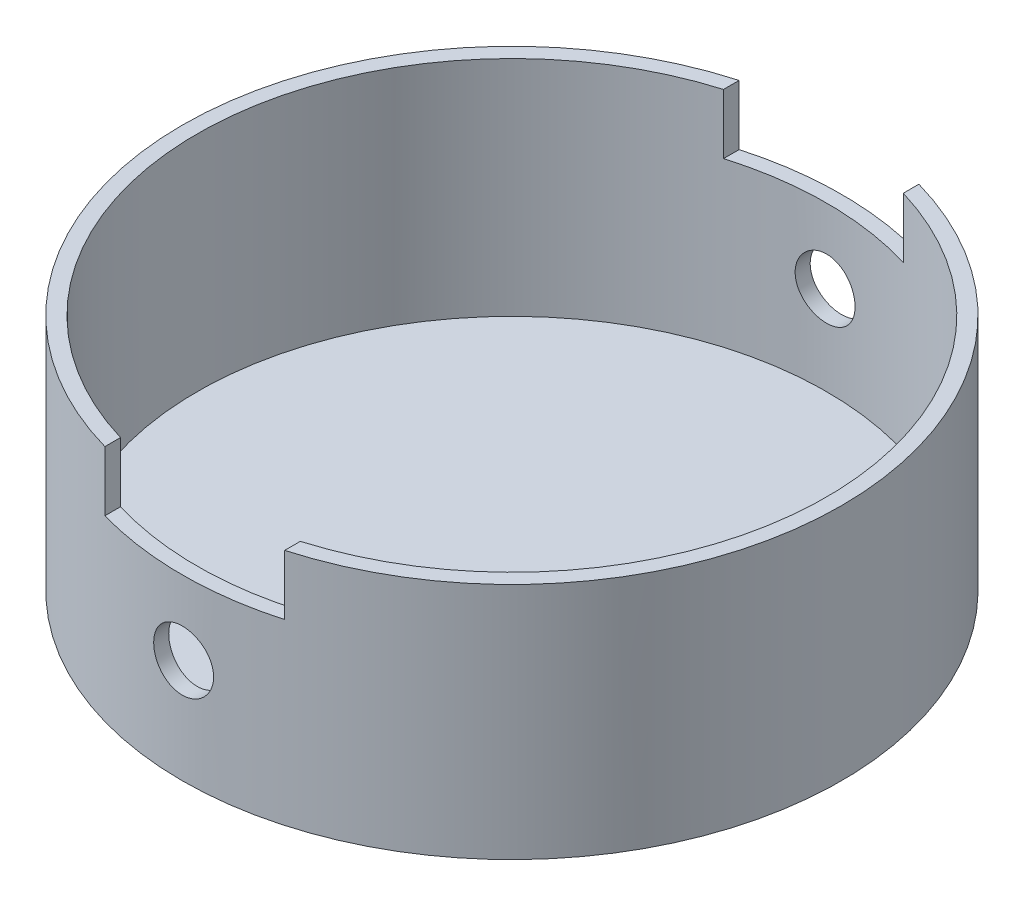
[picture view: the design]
ISO-10303-21;
HEADER;
FILE_DESCRIPTION(('STEP AP214'),'2;1');
FILE_NAME('part.step','',(''),(''),'','','');
FILE_SCHEMA(('AUTOMOTIVE_DESIGN { 1 0 10303 214 1 1 1 1 }'));
ENDSEC;
DATA;
#1=APPLICATION_CONTEXT('core data for automotive mechanical design processes');
#2=APPLICATION_PROTOCOL_DEFINITION('international standard','automotive_design',2000,#1);
#3=PRODUCT_CONTEXT('',#1,'mechanical');
#4=PRODUCT('Part','Part','',(#3));
#5=PRODUCT_RELATED_PRODUCT_CATEGORY('part','',(#4));
#6=PRODUCT_DEFINITION_FORMATION('','',#4);
#7=PRODUCT_DEFINITION_CONTEXT('part definition',#1,'design');
#8=PRODUCT_DEFINITION('design','',#6,#7);
#9=PRODUCT_DEFINITION_SHAPE('','',#8);
#10=(LENGTH_UNIT() NAMED_UNIT(*) SI_UNIT(.MILLI.,.METRE.));
#11=(NAMED_UNIT(*) PLANE_ANGLE_UNIT() SI_UNIT($,.RADIAN.));
#12=(NAMED_UNIT(*) SI_UNIT($,.STERADIAN.) SOLID_ANGLE_UNIT());
#13=UNCERTAINTY_MEASURE_WITH_UNIT(LENGTH_MEASURE(1.E-05),#10,'distance_accuracy_value','');
#14=(GEOMETRIC_REPRESENTATION_CONTEXT(3) GLOBAL_UNCERTAINTY_ASSIGNED_CONTEXT((#13)) GLOBAL_UNIT_ASSIGNED_CONTEXT((#10,
#11,#12)) REPRESENTATION_CONTEXT('',''));
#15=CARTESIAN_POINT('',(0.,0.,0.));
#16=DIRECTION('',(0.,0.,1.));
#17=DIRECTION('',(1.,0.,0.));
#18=AXIS2_PLACEMENT_3D('',#15,#16,#17);
#19=CARTESIAN_POINT('',(0.,50.4952,0.));
#20=DIRECTION('',(0.,1.,0.));
#21=DIRECTION('',(0.,0.,1.));
#22=AXIS2_PLACEMENT_3D('',#19,#20,#21);
#23=PLANE('',#22);
#24=DIRECTION('',(0.,0.,1.));
#25=VECTOR('',#24,1.);
#26=CARTESIAN_POINT('',(-19.05,50.4952,-69.85));
#27=LINE('',#26,#25);
#28=CARTESIAN_POINT('',(-19.05,50.4952,-67.2020833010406));
#29=VERTEX_POINT('',#28);
#30=CARTESIAN_POINT('',(-19.05,50.4952,-63.8956424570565));
#31=VERTEX_POINT('',#30);
#32=EDGE_CURVE('E112',#29,#31,#27,.T.);
#33=ORIENTED_EDGE('',*,*,#32,.F.);
#34=CARTESIAN_POINT('',(0.,50.4952,0.));
#35=DIRECTION('',(0.,1.,0.));
#36=DIRECTION('',(0.,0.,1.));
#37=AXIS2_PLACEMENT_3D('',#34,#35,#36);
#38=CIRCLE('',#37,69.85);
#39=CARTESIAN_POINT('',(-19.05,50.4952,67.2020833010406));
#40=VERTEX_POINT('',#39);
#41=EDGE_CURVE('E150',#29,#40,#38,.T.);
#42=ORIENTED_EDGE('',*,*,#41,.T.);
#43=CARTESIAN_POINT('',(-19.05,50.4952,63.8956424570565));
#44=VERTEX_POINT('',#43);
#45=EDGE_CURVE('E190',#44,#40,#27,.T.);
#46=ORIENTED_EDGE('',*,*,#45,.F.);
#47=CARTESIAN_POINT('',(0.,50.4952,0.));
#48=DIRECTION('',(0.,1.,0.));
#49=DIRECTION('',(0.,0.,1.));
#50=AXIS2_PLACEMENT_3D('',#47,#48,#49);
#51=CIRCLE('',#50,66.675);
#52=EDGE_CURVE('E145',#31,#44,#51,.T.);
#53=ORIENTED_EDGE('',*,*,#52,.F.);
#54=EDGE_LOOP('',(#33,#42,#46,#53));
#55=FACE_BOUND('',#54,.T.);
#56=ADVANCED_FACE('F31',(#55),#23,.T.);
#57=CARTESIAN_POINT('',(0.,50.4952,0.));
#58=DIRECTION('',(0.,-1.,0.));
#59=DIRECTION('',(0.,0.,-1.));
#60=AXIS2_PLACEMENT_3D('',#57,#58,#59);
#61=CYLINDRICAL_SURFACE('',#60,69.85);
#62=CARTESIAN_POINT('',(0.,28.4226,-69.85));
#63=CARTESIAN_POINT('',(-0.178010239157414,28.4226016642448,-69.8500004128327));
#64=CARTESIAN_POINT('',(-0.355994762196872,28.4151118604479,-69.8493181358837));
#65=CARTESIAN_POINT('',(-0.710752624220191,28.3852076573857,-69.8466089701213));
#66=CARTESIAN_POINT('',(-0.887525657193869,28.3627896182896,-69.8445817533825));
#67=CARTESIAN_POINT('',(-1.23868383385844,28.3031624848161,-69.8392370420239));
#68=CARTESIAN_POINT('',(-1.41306691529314,28.2659413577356,-69.8359184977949));
#69=CARTESIAN_POINT('',(-1.75812567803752,28.1769632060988,-69.8280837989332));
#70=CARTESIAN_POINT('',(-1.92879997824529,28.1252008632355,-69.8235672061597));
#71=CARTESIAN_POINT('',(-2.26500272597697,28.007576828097,-69.8134694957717));
#72=CARTESIAN_POINT('',(-2.43053592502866,27.9417286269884,-69.8078893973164));
#73=CARTESIAN_POINT('',(-2.75551943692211,27.7963497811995,-69.7958169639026));
#74=CARTESIAN_POINT('',(-2.9149674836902,27.7168140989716,-69.7893242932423));
#75=CARTESIAN_POINT('',(-3.22650420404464,27.5446948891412,-69.7756151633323));
#76=CARTESIAN_POINT('',(-3.37859709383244,27.452118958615,-69.7683991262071));
#77=CARTESIAN_POINT('',(-3.67451208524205,27.2545038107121,-69.7534402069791));
#78=CARTESIAN_POINT('',(-3.81833110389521,27.1494599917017,-69.7456971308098));
#79=CARTESIAN_POINT('',(-4.09695134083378,26.9274218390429,-69.7298860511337));
#80=CARTESIAN_POINT('',(-4.23173107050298,26.8104005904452,-69.7218173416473));
#81=CARTESIAN_POINT('',(-4.49101041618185,26.5653888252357,-69.705596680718));
#82=CARTESIAN_POINT('',(-4.61550621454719,26.4373942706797,-69.6974446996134));
#83=CARTESIAN_POINT('',(-4.85324696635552,26.1714168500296,-69.6812936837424));
#84=CARTESIAN_POINT('',(-4.96649554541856,26.0334372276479,-69.6732946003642));
#85=CARTESIAN_POINT('',(-5.1810275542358,25.7483703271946,-69.657670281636));
#86=CARTESIAN_POINT('',(-5.28230655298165,25.6012797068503,-69.6500451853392));
#87=CARTESIAN_POINT('',(-5.47226286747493,25.2988619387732,-69.6353784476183));
#88=CARTESIAN_POINT('',(-5.56092260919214,25.1435237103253,-69.6283376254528));
#89=CARTESIAN_POINT('',(-5.72486936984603,24.8258414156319,-69.6150496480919));
#90=CARTESIAN_POINT('',(-5.8001514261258,24.6634947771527,-69.6088027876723));
#91=CARTESIAN_POINT('',(-5.93673339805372,24.3330488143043,-69.5972873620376));
#92=CARTESIAN_POINT('',(-5.9980386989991,24.1649517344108,-69.5920184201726));
#93=CARTESIAN_POINT('',(-6.10627740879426,23.8241436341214,-69.5826040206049));
#94=CARTESIAN_POINT('',(-6.15320552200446,23.6514309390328,-69.578458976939));
#95=CARTESIAN_POINT('',(-6.271576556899,23.1293042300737,-69.5679269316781));
#96=CARTESIAN_POINT('',(-6.32113859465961,22.7746095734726,-69.5633965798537));
#97=CARTESIAN_POINT('',(-6.36002110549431,22.0621022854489,-69.5598516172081));
#98=CARTESIAN_POINT('',(-6.34934290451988,21.7042897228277,-69.5608368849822));
#99=CARTESIAN_POINT('',(-6.26826208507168,20.9965952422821,-69.5681897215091));
#100=CARTESIAN_POINT('',(-6.19803812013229,20.6466928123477,-69.5745411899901));
#101=CARTESIAN_POINT('',(-6.00011593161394,19.963675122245,-69.5918880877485));
#102=CARTESIAN_POINT('',(-5.87241705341,19.6305600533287,-69.6028835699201));
#103=CARTESIAN_POINT('',(-5.56297669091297,18.9899888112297,-69.6282974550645));
#104=CARTESIAN_POINT('',(-5.38115541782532,18.6825713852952,-69.6427209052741));
#105=CARTESIAN_POINT('',(-4.96868743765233,18.1025502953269,-69.6733612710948));
#106=CARTESIAN_POINT('',(-4.7380395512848,17.8299474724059,-69.6895782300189));
#107=CARTESIAN_POINT('',(-4.23346551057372,17.3262537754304,-69.7220500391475));
#108=CARTESIAN_POINT('',(-3.9593849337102,17.0953175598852,-69.7383048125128));
#109=CARTESIAN_POINT('',(-3.3762631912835,16.6827098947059,-69.7689647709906));
#110=CARTESIAN_POINT('',(-3.06722199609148,16.5010384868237,-69.7833699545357));
#111=CARTESIAN_POINT('',(-2.42284819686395,16.1921254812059,-69.8087112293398));
#112=CARTESIAN_POINT('',(-2.08751208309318,16.0648911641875,-69.8196468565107));
#113=CARTESIAN_POINT('',(-1.4001154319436,15.8685745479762,-69.8368118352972));
#114=CARTESIAN_POINT('',(-1.04805530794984,15.7994908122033,-69.8430413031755));
#115=CARTESIAN_POINT('',(-0.338544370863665,15.7216312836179,-69.8500771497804));
#116=CARTESIAN_POINT('',(0.0188828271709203,15.7126419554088,-69.8509027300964));
#117=CARTESIAN_POINT('',(0.730158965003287,15.7546664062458,-69.847089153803));
#118=CARTESIAN_POINT('',(1.0840079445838,15.8056795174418,-69.8424500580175));
#119=CARTESIAN_POINT('',(1.77747108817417,15.9660836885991,-69.828240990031));
#120=CARTESIAN_POINT('',(2.11710843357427,16.0753753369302,-69.8186794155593));
#121=CARTESIAN_POINT('',(2.77322639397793,16.3491324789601,-69.7956988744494));
#122=CARTESIAN_POINT('',(3.08970657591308,16.5135990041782,-69.7822798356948));
#123=CARTESIAN_POINT('',(3.69149557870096,16.8935705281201,-69.7530393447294));
#124=CARTESIAN_POINT('',(3.97671507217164,17.1092164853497,-69.7372113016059));
#125=CARTESIAN_POINT('',(4.50698344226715,17.5852237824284,-69.7049518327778));
#126=CARTESIAN_POINT('',(4.75203148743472,17.8455860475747,-69.6885203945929));
#127=CARTESIAN_POINT('',(5.1957377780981,18.4045593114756,-69.6568486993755));
#128=CARTESIAN_POINT('',(5.39425633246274,18.703281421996,-69.6416121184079));
#129=CARTESIAN_POINT('',(5.73830771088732,19.3299616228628,-69.6141095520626));
#130=CARTESIAN_POINT('',(5.88384114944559,19.657919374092,-69.6018435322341));
#131=CARTESIAN_POINT('',(6.11756176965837,20.3332069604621,-69.5816911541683));
#132=CARTESIAN_POINT('',(6.2058334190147,20.6805074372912,-69.5737983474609));
#133=CARTESIAN_POINT('',(6.32277396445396,21.3852702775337,-69.5632707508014));
#134=CARTESIAN_POINT('',(6.35144424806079,21.7427324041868,-69.5606358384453));
#135=CARTESIAN_POINT('',(6.34919308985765,22.2777191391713,-69.5608370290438));
#136=CARTESIAN_POINT('',(6.34093956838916,22.4556186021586,-69.5615927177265));
#137=CARTESIAN_POINT('',(6.3095350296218,22.8100690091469,-69.5644490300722));
#138=CARTESIAN_POINT('',(6.28638953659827,22.9866204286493,-69.5665491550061));
#139=CARTESIAN_POINT('',(6.22535142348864,23.3371887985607,-69.5720376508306));
#140=CARTESIAN_POINT('',(6.18745338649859,23.5112047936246,-69.5754264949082));
#141=CARTESIAN_POINT('',(6.09720538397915,23.8553549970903,-69.5833934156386));
#142=CARTESIAN_POINT('',(6.04486071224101,24.0254906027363,-69.5879710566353));
#143=CARTESIAN_POINT('',(5.92607389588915,24.3607852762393,-69.5981874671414));
#144=CARTESIAN_POINT('',(5.85962791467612,24.5259429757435,-69.6038265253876));
#145=CARTESIAN_POINT('',(5.71315046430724,24.850012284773,-69.6160025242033));
#146=CARTESIAN_POINT('',(5.63312396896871,25.0089261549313,-69.6225391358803));
#147=CARTESIAN_POINT('',(5.46000764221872,25.3195117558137,-69.6363292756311));
#148=CARTESIAN_POINT('',(5.36691324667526,25.4711809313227,-69.6435830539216));
#149=CARTESIAN_POINT('',(5.16837734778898,25.7661028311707,-69.6585980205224));
#150=CARTESIAN_POINT('',(5.06294034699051,25.9093585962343,-69.6663590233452));
#151=CARTESIAN_POINT('',(4.84000302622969,26.1870496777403,-69.6822029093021));
#152=CARTESIAN_POINT('',(4.72245768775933,26.321448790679,-69.690286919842));
#153=CARTESIAN_POINT('',(4.47651818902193,26.5798258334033,-69.7065166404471));
#154=CARTESIAN_POINT('',(4.34812801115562,26.7038075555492,-69.7146623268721));
#155=CARTESIAN_POINT('',(4.08128283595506,26.9406046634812,-69.7307930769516));
#156=CARTESIAN_POINT('',(3.94282174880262,27.0534131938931,-69.7387780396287));
#157=CARTESIAN_POINT('',(3.65693105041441,27.2669407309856,-69.754353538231));
#158=CARTESIAN_POINT('',(3.50950476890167,27.3676641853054,-69.761944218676));
#159=CARTESIAN_POINT('',(3.20629253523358,27.5565926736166,-69.776538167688));
#160=CARTESIAN_POINT('',(3.05048647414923,27.6447655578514,-69.7835399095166));
#161=CARTESIAN_POINT('',(2.73201989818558,27.8076277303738,-69.7967331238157));
#162=CARTESIAN_POINT('',(2.56936191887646,27.88232195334,-69.8029248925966));
#163=CARTESIAN_POINT('',(2.23842723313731,28.0176712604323,-69.8143203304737));
#164=CARTESIAN_POINT('',(2.07015532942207,28.0783380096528,-69.819524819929));
#165=CARTESIAN_POINT('',(1.72912198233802,28.1852567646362,-69.8288031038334));
#166=CARTESIAN_POINT('',(1.55636166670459,28.2315123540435,-69.8328771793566));
#167=CARTESIAN_POINT('',(1.15536287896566,28.3209189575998,-69.8408112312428));
#168=CARTESIAN_POINT('',(0.925970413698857,28.3590134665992,-69.8442435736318));
#169=CARTESIAN_POINT('',(0.46437071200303,28.4098528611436,-69.848837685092));
#170=CARTESIAN_POINT('',(0.232163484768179,28.4225978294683,-69.8499994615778));
#171=CARTESIAN_POINT('',(0.,28.4226,-69.85));
#172=B_SPLINE_CURVE_WITH_KNOTS('',3,(#62,#63,#64,#65,#66,#67,#68,#69,#70,#71,#72,#73,#74,#75,
#76,#77,#78,#79,#80,#81,#82,#83,#84,#85,#86,#87,#88,#89,#90,#91,#92,#93,#94,#95,#96,#97,#98,#99,
#100,#101,#102,#103,#104,#105,#106,#107,#108,#109,#110,#111,#112,#113,#114,#115,#116,#117,#118,
#119,#120,#121,#122,#123,#124,#125,#126,#127,#128,#129,#130,#131,#132,#133,#134,#135,#136,#137,
#138,#139,#140,#141,#142,#143,#144,#145,#146,#147,#148,#149,#150,#151,#152,#153,#154,#155,#156,
#157,#158,#159,#160,#161,#162,#163,#164,#165,#166,#167,#168,#169,#170,#171),.UNSPECIFIED.,.T.,
.F.,(4,2,2,2,2,2,2,2,2,2,2,2,2,2,2,2,2,2,2,2,2,2,2,2,2,2,2,2,2,2,2,2,2,2,2,2,2,2,2,2,2,2,2,2,2,
2,2,2,2,2,2,2,2,2,4),(0.,0.533827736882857,1.06778568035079,1.60217854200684,2.13676710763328,
2.67084592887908,3.20512173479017,3.73908755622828,4.27325106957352,4.80864243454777,
5.34423166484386,5.8796476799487,6.41526128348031,6.95161365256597,7.48816457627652,
8.02450841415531,8.56104957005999,9.62999055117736,10.6989080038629,11.7646297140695,
12.8303635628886,13.8976763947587,14.9650150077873,16.036237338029,17.1074605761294,
18.1788270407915,19.250167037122,20.3176981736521,21.3852174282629,22.4509215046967,
23.5166455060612,24.5853395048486,25.6540556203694,26.7259402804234,27.7978125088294,
28.8680999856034,29.9383625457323,30.4721205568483,31.0056806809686,31.539436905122,
32.0729977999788,32.6067040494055,33.1402152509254,33.6739132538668,34.2074171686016,
34.742981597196,35.2783502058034,35.8140452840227,36.3495426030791,36.8863878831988,
37.4230362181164,37.9592366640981,38.495303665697,39.1915316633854,39.8877573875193),.UNSPECIFIED.);
#173=CARTESIAN_POINT('',(0.,28.4226,-69.85));
#174=VERTEX_POINT('',#173);
#175=EDGE_CURVE('E134',#174,#174,#172,.T.);
#176=ORIENTED_EDGE('',*,*,#175,.T.);
#177=EDGE_LOOP('',(#176));
#178=FACE_BOUND('',#177,.T.);
#179=CARTESIAN_POINT('',(6.35,22.0726,69.5607648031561));
#180=CARTESIAN_POINT('',(6.35000166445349,21.8945914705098,69.5607643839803));
#181=CARTESIAN_POINT('',(6.34251200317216,21.716608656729,69.5614495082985));
#182=CARTESIAN_POINT('',(6.31260838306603,21.3618542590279,69.5641697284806));
#183=CARTESIAN_POINT('',(6.2901907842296,21.1850829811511,69.5662051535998));
#184=CARTESIAN_POINT('',(6.23056485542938,20.8339283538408,69.5715707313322));
#185=CARTESIAN_POINT('',(6.19334449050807,20.6595470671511,69.5749019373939));
#186=CARTESIAN_POINT('',(6.10436821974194,20.3144919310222,69.5827649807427));
#187=CARTESIAN_POINT('',(6.05260699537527,20.1438194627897,69.5872972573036));
#188=CARTESIAN_POINT('',(5.93498566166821,19.807620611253,69.5974275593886));
#189=CARTESIAN_POINT('',(5.86913906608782,19.6420894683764,69.6030245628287));
#190=CARTESIAN_POINT('',(5.7237638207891,19.3171098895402,69.615130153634));
#191=CARTESIAN_POINT('',(5.6442301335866,19.1576637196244,69.6216390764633));
#192=CARTESIAN_POINT('',(5.472115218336,18.8461304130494,69.6353782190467));
#193=CARTESIAN_POINT('',(5.37954158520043,18.69403906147,69.6426080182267));
#194=CARTESIAN_POINT('',(5.18193124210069,18.3981267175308,69.6575904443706));
#195=CARTESIAN_POINT('',(5.07688993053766,18.2543088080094,69.6653432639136));
#196=CARTESIAN_POINT('',(4.85485427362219,17.9756870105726,69.6811689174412));
#197=CARTESIAN_POINT('',(4.73783273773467,17.8409048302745,69.6892424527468));
#198=CARTESIAN_POINT('',(4.49281987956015,17.5816205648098,69.7054671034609));
#199=CARTESIAN_POINT('',(4.36482451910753,17.4571222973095,69.7136182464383));
#200=CARTESIAN_POINT('',(4.09884499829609,17.2193767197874,69.7297620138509));
#201=CARTESIAN_POINT('',(3.96086408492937,17.1061257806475,69.7377546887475));
#202=CARTESIAN_POINT('',(3.67579412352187,16.891589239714,69.7533613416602));
#203=CARTESIAN_POINT('',(3.52870173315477,16.7903080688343,69.7609751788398));
#204=CARTESIAN_POINT('',(3.22628259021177,16.6003493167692,69.7756156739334));
#205=CARTESIAN_POINT('',(3.07094489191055,16.5116890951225,69.7826415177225));
#206=CARTESIAN_POINT('',(2.753263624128,16.3477413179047,69.7958976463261));
#207=CARTESIAN_POINT('',(2.59091748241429,16.2724587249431,69.802127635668));
#208=CARTESIAN_POINT('',(2.26047253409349,16.1358756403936,69.8136093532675));
#209=CARTESIAN_POINT('',(2.09237597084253,16.0745697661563,69.8188614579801));
#210=CARTESIAN_POINT('',(1.75156900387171,15.9663298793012,69.8282440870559));
#211=CARTESIAN_POINT('',(1.57885692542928,15.9194011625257,69.8323741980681));
#212=CARTESIAN_POINT('',(1.05673284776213,15.8010283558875,69.8428670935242));
#213=CARTESIAN_POINT('',(0.702040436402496,15.7514649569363,69.8473787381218));
#214=CARTESIAN_POINT('',(-0.0104624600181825,15.7125789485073,69.8509094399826));
#215=CARTESIAN_POINT('',(-0.368272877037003,15.7232550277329,69.8499286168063));
#216=CARTESIAN_POINT('',(-1.07597673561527,15.80433249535,69.8426057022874));
#217=CARTESIAN_POINT('',(-1.42589044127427,15.8745573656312,69.8362794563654));
#218=CARTESIAN_POINT('',(-2.10893021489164,16.0724852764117,69.8189927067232));
#219=CARTESIAN_POINT('',(-2.44205609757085,16.2001889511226,69.808032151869));
#220=CARTESIAN_POINT('',(-3.08264041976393,16.5096392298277,69.7826829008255));
#221=CARTESIAN_POINT('',(-3.39006065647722,16.6914645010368,69.7682892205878));
#222=CARTESIAN_POINT('',(-3.9700856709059,17.1039410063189,69.7376900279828));
#223=CARTESIAN_POINT('',(-4.24268960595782,17.3345934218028,69.7214844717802));
#224=CARTESIAN_POINT('',(-4.74637815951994,17.8391706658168,69.6890124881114));
#225=CARTESIAN_POINT('',(-4.97730903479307,18.1132489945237,69.6727460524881));
#226=CARTESIAN_POINT('',(-5.38990699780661,18.6963643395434,69.6420443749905));
#227=CARTESIAN_POINT('',(-5.57157403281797,19.0054013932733,69.6276091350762));
#228=CARTESIAN_POINT('',(-5.88048389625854,19.649774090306,69.6022022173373));
#229=CARTESIAN_POINT('',(-6.00771809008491,19.9851138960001,69.591231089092));
#230=CARTESIAN_POINT('',(-6.204033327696,20.6725185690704,69.5740056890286));
#231=CARTESIAN_POINT('',(-6.27311583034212,21.0245830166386,69.5677512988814));
#232=CARTESIAN_POINT('',(-6.35097071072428,21.7340959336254,69.560687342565));
#233=CARTESIAN_POINT('',(-6.35995778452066,22.0915206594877,69.5598583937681));
#234=CARTESIAN_POINT('',(-6.31792970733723,22.8027913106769,69.5636880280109));
#235=CARTESIAN_POINT('',(-6.26691522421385,23.1566372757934,69.5683465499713));
#236=CARTESIAN_POINT('',(-6.10651143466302,23.8500855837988,69.5826085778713));
#237=CARTESIAN_POINT('',(-5.99722289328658,24.1897114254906,69.5922035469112));
#238=CARTESIAN_POINT('',(-5.72347581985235,24.8458077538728,69.615250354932));
#239=CARTESIAN_POINT('',(-5.55901623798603,25.1622777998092,69.6287022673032));
#240=CARTESIAN_POINT('',(-5.17905490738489,25.7640599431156,69.6579942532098));
#241=CARTESIAN_POINT('',(-4.96341043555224,26.0492815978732,69.6738409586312));
#242=CARTESIAN_POINT('',(-4.48740485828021,26.5795550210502,69.7061148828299));
#243=CARTESIAN_POINT('',(-4.22704283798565,26.8246059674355,69.7225421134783));
#244=CARTESIAN_POINT('',(-3.66806829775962,27.2683184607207,69.754184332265));
#245=CARTESIAN_POINT('',(-3.36934462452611,27.4668402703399,69.7693955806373));
#246=CARTESIAN_POINT('',(-2.74266043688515,27.8108973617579,69.7968374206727));
#247=CARTESIAN_POINT('',(-2.41470026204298,27.956433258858,69.809068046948));
#248=CARTESIAN_POINT('',(-1.73941425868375,28.1901555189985,69.8291549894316));
#249=CARTESIAN_POINT('',(-1.39211815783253,28.278427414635,69.8370178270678));
#250=CARTESIAN_POINT('',(-0.687364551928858,28.3953699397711,69.8475044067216));
#251=CARTESIAN_POINT('',(-0.329907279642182,28.4240419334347,69.8501282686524));
#252=CARTESIAN_POINT('',(0.205078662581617,28.4217945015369,69.8499281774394));
#253=CARTESIAN_POINT('',(0.382981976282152,28.4135418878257,69.8491757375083));
#254=CARTESIAN_POINT('',(0.737440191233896,28.3821385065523,69.8463311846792));
#255=CARTESIAN_POINT('',(0.913995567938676,28.3589932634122,69.8442395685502));
#256=CARTESIAN_POINT('',(1.26457190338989,28.297954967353,69.8387724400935));
#257=CARTESIAN_POINT('',(1.43859190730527,28.2600565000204,69.835396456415));
#258=CARTESIAN_POINT('',(1.78275012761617,28.1698069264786,69.8274581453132));
#259=CARTESIAN_POINT('',(1.95288974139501,28.1174611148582,69.8228962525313));
#260=CARTESIAN_POINT('',(2.28819250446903,27.9986712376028,69.8127124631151));
#261=CARTESIAN_POINT('',(2.45335427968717,27.932223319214,69.807090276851));
#262=CARTESIAN_POINT('',(2.77743143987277,27.7857412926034,69.7949472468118));
#263=CARTESIAN_POINT('',(2.93634908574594,27.7057121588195,69.7884267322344));
#264=CARTESIAN_POINT('',(3.24694175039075,27.5325899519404,69.7746662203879));
#265=CARTESIAN_POINT('',(3.39861421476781,27.4394923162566,69.7674259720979));
#266=CARTESIAN_POINT('',(3.69354207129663,27.2409494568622,69.7524339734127));
#267=CARTESIAN_POINT('',(3.83680050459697,27.1355087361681,69.7446824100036));
#268=CARTESIAN_POINT('',(4.11449136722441,26.9125675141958,69.7288525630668));
#269=CARTESIAN_POINT('',(4.2488879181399,26.795022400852,69.7207731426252));
#270=CARTESIAN_POINT('',(4.50725981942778,26.5490838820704,69.7045469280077));
#271=CARTESIAN_POINT('',(4.6312389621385,26.4206944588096,69.6964001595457));
#272=CARTESIAN_POINT('',(4.86803101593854,26.1538512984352,69.6802616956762));
#273=CARTESIAN_POINT('',(4.98083706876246,26.0153914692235,69.6722700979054));
#274=CARTESIAN_POINT('',(5.19435984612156,25.7295037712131,69.6566765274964));
#275=CARTESIAN_POINT('',(5.29508101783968,25.582079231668,69.6490744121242));
#276=CARTESIAN_POINT('',(5.48400689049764,25.27886823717,69.6344539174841));
#277=CARTESIAN_POINT('',(5.57217921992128,25.123061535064,69.6274370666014));
#278=CARTESIAN_POINT('',(5.73504021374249,24.8045937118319,69.614211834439));
#279=CARTESIAN_POINT('',(5.80973381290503,24.6419351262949,69.6080031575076));
#280=CARTESIAN_POINT('',(5.94508181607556,24.3109992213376,69.596574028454));
#281=CARTESIAN_POINT('',(6.00574788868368,24.1427267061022,69.591352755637));
#282=CARTESIAN_POINT('',(6.11266524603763,23.8016920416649,69.5820429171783));
#283=CARTESIAN_POINT('',(6.15892011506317,23.6289310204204,69.5779540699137));
#284=CARTESIAN_POINT('',(6.24832360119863,23.2279366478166,69.5699904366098));
#285=CARTESIAN_POINT('',(6.28641636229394,22.9985494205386,69.5665444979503));
#286=CARTESIAN_POINT('',(6.33725343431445,22.536960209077,69.5619319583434));
#287=CARTESIAN_POINT('',(6.34999782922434,22.3047582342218,69.5607653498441));
#288=CARTESIAN_POINT('',(6.35,22.0726,69.5607648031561));
#289=B_SPLINE_CURVE_WITH_KNOTS('',3,(#179,#180,#181,#182,#183,#184,#185,#186,#187,#188,#189,
#190,#191,#192,#193,#194,#195,#196,#197,#198,#199,#200,#201,#202,#203,#204,#205,#206,#207,#208,
#209,#210,#211,#212,#213,#214,#215,#216,#217,#218,#219,#220,#221,#222,#223,#224,#225,#226,#227,
#228,#229,#230,#231,#232,#233,#234,#235,#236,#237,#238,#239,#240,#241,#242,#243,#244,#245,#246,
#247,#248,#249,#250,#251,#252,#253,#254,#255,#256,#257,#258,#259,#260,#261,#262,#263,#264,#265,
#266,#267,#268,#269,#270,#271,#272,#273,#274,#275,#276,#277,#278,#279,#280,#281,#282,#283,#284,
#285,#286,#287,#288),.UNSPECIFIED.,.T.,.F.,(4,2,2,2,2,2,2,2,2,2,2,2,2,2,2,2,2,2,2,2,2,2,2,2,2,2,
2,2,2,2,2,2,2,2,2,2,2,2,2,2,2,2,2,2,2,2,2,2,2,2,2,2,2,2,4),(0.,0.533822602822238,
1.06777542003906,1.60216324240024,2.13674677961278,2.67081970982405,3.205089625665,
3.73904964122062,4.27320734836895,4.80860546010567,5.34420144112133,5.87962403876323,
6.41524421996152,6.95159414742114,7.48814262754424,8.02448412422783,8.56102294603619,
9.62995750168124,10.6988687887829,11.7646225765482,12.8303881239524,13.8977104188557,
14.9650585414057,16.0362672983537,17.1074772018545,18.1788569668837,19.250209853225,
20.3177331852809,21.385244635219,22.4509161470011,23.5166079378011,24.5853069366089,
25.6540278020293,26.7259182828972,27.7977963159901,28.8680696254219,29.9383184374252,
30.4720878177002,31.0056593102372,31.539426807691,32.0729989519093,32.6067170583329,
33.1402400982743,33.673949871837,34.2074655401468,34.743023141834,35.2783849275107,
35.8140733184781,36.349563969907,36.8864118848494,37.4230628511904,37.9592657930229,
38.4953352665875,39.1915475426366,39.8877575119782),.UNSPECIFIED.);
#290=CARTESIAN_POINT('',(6.35,22.0726,69.5607648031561));
#291=VERTEX_POINT('',#290);
#292=EDGE_CURVE('E183',#291,#291,#289,.T.);
#293=ORIENTED_EDGE('',*,*,#292,.T.);
#294=EDGE_LOOP('',(#293));
#295=FACE_BOUND('',#294,.T.);
#296=CARTESIAN_POINT('',(19.05,50.4952,67.2020833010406));
#297=VERTEX_POINT('',#296);
#298=CARTESIAN_POINT('',(19.05,50.4952,-67.2020833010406));
#299=VERTEX_POINT('',#298);
#300=EDGE_CURVE('E153',#297,#299,#38,.T.);
#301=ORIENTED_EDGE('',*,*,#300,.F.);
#302=DIRECTION('',(0.,-1.,0.));
#303=VECTOR('',#302,1.);
#304=CARTESIAN_POINT('',(19.05,50.4952,67.2020833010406));
#305=LINE('',#304,#303);
#306=CARTESIAN_POINT('',(19.05,37.7952,67.2020833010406));
#307=VERTEX_POINT('',#306);
#308=EDGE_CURVE('E121',#297,#307,#305,.T.);
#309=ORIENTED_EDGE('',*,*,#308,.T.);
#310=CARTESIAN_POINT('',(0.,37.7952,0.));
#311=DIRECTION('',(0.,-1.,0.));
#312=DIRECTION('',(1.,0.,0.));
#313=AXIS2_PLACEMENT_3D('',#310,#311,#312);
#314=CIRCLE('',#313,69.85);
#315=CARTESIAN_POINT('',(-19.05,37.7952,67.2020833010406));
#316=VERTEX_POINT('',#315);
#317=EDGE_CURVE('E111',#307,#316,#314,.T.);
#318=ORIENTED_EDGE('',*,*,#317,.T.);
#319=DIRECTION('',(0.,-1.,0.));
#320=VECTOR('',#319,1.);
#321=CARTESIAN_POINT('',(-19.05,50.4952,67.2020833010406));
#322=LINE('',#321,#320);
#323=EDGE_CURVE('E138',#316,#40,#322,.F.);
#324=ORIENTED_EDGE('',*,*,#323,.T.);
#325=ORIENTED_EDGE('',*,*,#41,.F.);
#326=DIRECTION('',(0.,-1.,0.));
#327=VECTOR('',#326,1.);
#328=CARTESIAN_POINT('',(-19.05,50.4952,-67.2020833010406));
#329=LINE('',#328,#327);
#330=CARTESIAN_POINT('',(-19.05,37.7952,-67.2020833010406));
#331=VERTEX_POINT('',#330);
#332=EDGE_CURVE('E109',#29,#331,#329,.T.);
#333=ORIENTED_EDGE('',*,*,#332,.T.);
#334=CARTESIAN_POINT('',(19.05,37.7952,-67.2020833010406));
#335=VERTEX_POINT('',#334);
#336=EDGE_CURVE('E102',#331,#335,#314,.T.);
#337=ORIENTED_EDGE('',*,*,#336,.T.);
#338=DIRECTION('',(0.,-1.,0.));
#339=VECTOR('',#338,1.);
#340=CARTESIAN_POINT('',(19.05,50.4952,-67.2020833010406));
#341=LINE('',#340,#339);
#342=EDGE_CURVE('E106',#335,#299,#341,.F.);
#343=ORIENTED_EDGE('',*,*,#342,.T.);
#344=EDGE_LOOP('',(#301,#309,#318,#324,#325,#333,#337,#343));
#345=FACE_BOUND('',#344,.T.);
#346=CARTESIAN_POINT('',(0.,0.,0.));
#347=DIRECTION('',(0.,1.,0.));
#348=DIRECTION('',(0.,0.,1.));
#349=AXIS2_PLACEMENT_3D('',#346,#347,#348);
#350=CIRCLE('',#349,69.85);
#351=CARTESIAN_POINT('',(0.,0.,69.85));
#352=VERTEX_POINT('',#351);
#353=EDGE_CURVE('E149',#352,#352,#350,.T.);
#354=ORIENTED_EDGE('',*,*,#353,.T.);
#355=EDGE_LOOP('',(#354));
#356=FACE_BOUND('',#355,.T.);
#357=ADVANCED_FACE('F33',(#178,#295,#345,#356),#61,.T.);
#358=DIRECTION('',(0.,0.,1.));
#359=VECTOR('',#358,1.);
#360=CARTESIAN_POINT('',(19.05,50.4952,-69.85));
#361=LINE('',#360,#359);
#362=CARTESIAN_POINT('',(19.05,50.4952,63.8956424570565));
#363=VERTEX_POINT('',#362);
#364=EDGE_CURVE('E126',#363,#297,#361,.T.);
#365=ORIENTED_EDGE('',*,*,#364,.T.);
#366=ORIENTED_EDGE('',*,*,#300,.T.);
#367=CARTESIAN_POINT('',(19.05,50.4952,-63.8956424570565));
#368=VERTEX_POINT('',#367);
#369=EDGE_CURVE('E120',#299,#368,#361,.T.);
#370=ORIENTED_EDGE('',*,*,#369,.T.);
#371=EDGE_CURVE('E146',#363,#368,#51,.T.);
#372=ORIENTED_EDGE('',*,*,#371,.F.);
#373=EDGE_LOOP('',(#365,#366,#370,#372));
#374=FACE_BOUND('',#373,.T.);
#375=ADVANCED_FACE('F196',(#374),#23,.T.);
#376=CARTESIAN_POINT('',(0.,0.,0.));
#377=DIRECTION('',(0.,1.,0.));
#378=DIRECTION('',(0.,0.,1.));
#379=AXIS2_PLACEMENT_3D('',#376,#377,#378);
#380=PLANE('',#379);
#381=ORIENTED_EDGE('',*,*,#353,.F.);
#382=EDGE_LOOP('',(#381));
#383=FACE_BOUND('',#382,.T.);
#384=ADVANCED_FACE('F223',(#383),#380,.F.);
#385=CARTESIAN_POINT('',(0.,50.4952,0.));
#386=DIRECTION('',(0.,-1.,0.));
#387=DIRECTION('',(0.,0.,-1.));
#388=AXIS2_PLACEMENT_3D('',#385,#386,#387);
#389=CYLINDRICAL_SURFACE('',#388,66.675);
#390=CARTESIAN_POINT('',(0.,28.4226,-66.675));
#391=CARTESIAN_POINT('',(-0.177971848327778,28.42260170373,-66.6750004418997));
#392=CARTESIAN_POINT('',(-0.35591752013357,28.4151151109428,-66.6742859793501));
#393=CARTESIAN_POINT('',(-0.710597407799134,28.3852239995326,-66.6714490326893));
#394=CARTESIAN_POINT('',(-0.887331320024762,28.3628158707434,-66.6693262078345));
#395=CARTESIAN_POINT('',(-1.23840966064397,28.3032157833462,-66.6637294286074));
#396=CARTESIAN_POINT('',(-1.41275204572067,28.266011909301,-66.6602543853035));
#397=CARTESIAN_POINT('',(-1.75772963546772,28.1770759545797,-66.6520501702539));
#398=CARTESIAN_POINT('',(-1.92836345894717,28.1253385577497,-66.6473205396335));
#399=CARTESIAN_POINT('',(-2.26448447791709,28.0077731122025,-66.6367464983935));
#400=CARTESIAN_POINT('',(-2.42997647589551,27.9419586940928,-66.630903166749));
#401=CARTESIAN_POINT('',(-2.75487979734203,27.7966560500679,-66.6182610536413));
#402=CARTESIAN_POINT('',(-2.91428885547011,27.7171627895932,-66.6114619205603));
#403=CARTESIAN_POINT('',(-3.22575193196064,27.545136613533,-66.5971053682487));
#404=CARTESIAN_POINT('',(-3.37781013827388,27.4526112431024,-66.5895483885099));
#405=CARTESIAN_POINT('',(-3.67366118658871,27.2551051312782,-66.573882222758));
#406=CARTESIAN_POINT('',(-3.81745094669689,27.1501197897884,-66.5657728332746));
#407=CARTESIAN_POINT('',(-4.09605433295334,26.9281781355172,-66.5492110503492));
#408=CARTESIAN_POINT('',(-4.23084416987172,26.8111920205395,-66.5407578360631));
#409=CARTESIAN_POINT('',(-4.49014733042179,26.5662507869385,-66.5237633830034));
#410=CARTESIAN_POINT('',(-4.61465683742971,26.4382916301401,-66.5152221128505));
#411=CARTESIAN_POINT('',(-4.85242944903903,26.1723839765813,-66.4982989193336));
#412=CARTESIAN_POINT('',(-4.96569617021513,26.0344387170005,-66.4899169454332));
#413=CARTESIAN_POINT('',(-5.18026920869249,25.7494382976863,-66.4735437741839));
#414=CARTESIAN_POINT('',(-5.2815710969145,25.6023797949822,-66.4655527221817));
#415=CARTESIAN_POINT('',(-5.47159464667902,25.2999961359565,-66.4501797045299));
#416=CARTESIAN_POINT('',(-5.5602965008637,25.1446584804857,-66.4427987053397));
#417=CARTESIAN_POINT('',(-5.72432698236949,24.8269703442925,-66.4288678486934));
#418=CARTESIAN_POINT('',(-5.79965064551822,24.6646172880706,-66.4223183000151));
#419=CARTESIAN_POINT('',(-5.93631413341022,24.3341515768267,-66.4102440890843));
#420=CARTESIAN_POINT('',(-5.99765936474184,24.1660411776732,-66.4047190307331));
#421=CARTESIAN_POINT('',(-6.10597519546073,23.8251997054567,-66.3948462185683));
#422=CARTESIAN_POINT('',(-6.15294050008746,23.6524669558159,-66.3904988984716));
#423=CARTESIAN_POINT('',(-6.27139561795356,23.1303652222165,-66.3794536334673));
#424=CARTESIAN_POINT('',(-6.32101460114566,22.7757103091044,-66.374700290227));
#425=CARTESIAN_POINT('',(-6.36002120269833,22.0632698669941,-66.3709732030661));
#426=CARTESIAN_POINT('',(-6.34941026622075,21.7054844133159,-66.3719993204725));
#427=CARTESIAN_POINT('',(-6.26848538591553,20.9979419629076,-66.3796907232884));
#428=CARTESIAN_POINT('',(-6.19836766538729,20.6481624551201,-66.38633747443));
#429=CARTESIAN_POINT('',(-6.00070378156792,19.9653728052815,-66.4044948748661));
#430=CARTESIAN_POINT('',(-5.87315690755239,19.6323628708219,-66.4160055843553));
#431=CARTESIAN_POINT('',(-5.56404332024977,18.9919267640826,-66.4426145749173));
#432=CARTESIAN_POINT('',(-5.38238922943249,18.6845430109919,-66.4577186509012));
#433=CARTESIAN_POINT('',(-4.9702790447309,18.1045534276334,-66.4898076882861));
#434=CARTESIAN_POINT('',(-4.73982165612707,17.8319485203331,-66.5067926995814));
#435=CARTESIAN_POINT('',(-4.23554945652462,17.3281128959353,-66.540812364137));
#436=CARTESIAN_POINT('',(-3.9615650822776,17.0970518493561,-66.5578469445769));
#437=CARTESIAN_POINT('',(-3.37860584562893,16.6841773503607,-66.5899821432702));
#438=CARTESIAN_POINT('',(-3.06963094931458,16.5023639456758,-66.6050827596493));
#439=CARTESIAN_POINT('',(-2.4253460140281,16.1931536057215,-66.6316528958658));
#440=CARTESIAN_POINT('',(-2.09003197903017,16.0657649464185,-66.6431218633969));
#441=CARTESIAN_POINT('',(-1.4026410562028,15.8691428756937,-66.6611306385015));
#442=CARTESIAN_POINT('',(-1.05056462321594,15.7999078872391,-66.6676705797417));
#443=CARTESIAN_POINT('',(-0.341112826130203,15.7217729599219,-66.6750672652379));
#444=CARTESIAN_POINT('',(0.0162365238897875,15.7126388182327,-66.6759460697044));
#445=CARTESIAN_POINT('',(0.727381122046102,15.7543502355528,-66.6719805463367));
#446=CARTESIAN_POINT('',(1.08117641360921,15.8051950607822,-66.6671362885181));
#447=CARTESIAN_POINT('',(1.77449646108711,15.9652268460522,-66.6522832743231));
#448=CARTESIAN_POINT('',(2.11404667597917,16.0743044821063,-66.6422841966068));
#449=CARTESIAN_POINT('',(2.77002851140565,16.3475935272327,-66.6182437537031));
#450=CARTESIAN_POINT('',(3.08645965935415,16.5118060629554,-66.604202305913));
#451=CARTESIAN_POINT('',(3.6882820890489,16.89128634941,-66.5735938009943));
#452=CARTESIAN_POINT('',(3.97357570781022,17.1067083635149,-66.557019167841));
#453=CARTESIAN_POINT('',(4.5040367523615,17.5822721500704,-66.5232295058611));
#454=CARTESIAN_POINT('',(4.74920326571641,17.842414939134,-66.5060144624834));
#455=CARTESIAN_POINT('',(5.19326140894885,18.4010512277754,-66.4728180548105));
#456=CARTESIAN_POINT('',(5.39199959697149,18.6996669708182,-66.4568408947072));
#457=CARTESIAN_POINT('',(5.73650382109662,19.3261857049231,-66.4279923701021));
#458=CARTESIAN_POINT('',(5.88227052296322,19.6540883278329,-66.4151209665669));
#459=CARTESIAN_POINT('',(6.11644252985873,20.3292749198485,-66.3939652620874));
#460=CARTESIAN_POINT('',(6.20493992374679,20.6765267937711,-66.3856736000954));
#461=CARTESIAN_POINT('',(6.32233505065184,21.3812389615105,-66.3745986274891));
#462=CARTESIAN_POINT('',(6.35123432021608,21.7386989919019,-66.3718151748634));
#463=CARTESIAN_POINT('',(6.34932179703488,22.2736466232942,-66.3719936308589));
#464=CARTESIAN_POINT('',(6.34118571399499,22.4514951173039,-66.372774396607));
#465=CARTESIAN_POINT('',(6.31002474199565,22.8058532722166,-66.3757448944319));
#466=CARTESIAN_POINT('',(6.28700537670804,22.9823634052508,-66.3779341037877));
#467=CARTESIAN_POINT('',(6.22622772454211,23.3328590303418,-66.3836623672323));
#468=CARTESIAN_POINT('',(6.1884640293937,23.5068435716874,-66.3872019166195));
#469=CARTESIAN_POINT('',(6.09849239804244,23.8509413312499,-66.3955273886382));
#470=CARTESIAN_POINT('',(6.04628974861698,24.0210559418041,-66.4003128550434));
#471=CARTESIAN_POINT('',(5.92779559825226,24.3563160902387,-66.4109960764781));
#472=CARTESIAN_POINT('',(5.86150057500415,24.5214603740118,-66.4168941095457));
#473=CARTESIAN_POINT('',(5.71533216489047,24.8455155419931,-66.4296317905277));
#474=CARTESIAN_POINT('',(5.63546374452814,25.0044286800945,-66.436471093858));
#475=CARTESIAN_POINT('',(5.4626696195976,25.3150272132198,-66.4509020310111));
#476=CARTESIAN_POINT('',(5.36973932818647,25.4667100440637,-66.4584939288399));
#477=CARTESIAN_POINT('',(5.17153619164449,25.7616750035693,-66.474210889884));
#478=CARTESIAN_POINT('',(5.06626784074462,25.9049601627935,-66.482335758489));
#479=CARTESIAN_POINT('',(4.84363231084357,26.1827759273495,-66.4989275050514));
#480=CARTESIAN_POINT('',(4.72621604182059,26.3172671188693,-66.507395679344));
#481=CARTESIAN_POINT('',(4.48052762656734,26.5758395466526,-66.5243989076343));
#482=CARTESIAN_POINT('',(4.35225946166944,26.6999245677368,-66.5329339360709));
#483=CARTESIAN_POINT('',(4.08564971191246,26.9369396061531,-66.5498380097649));
#484=CARTESIAN_POINT('',(3.94730203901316,27.0498627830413,-66.5582069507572));
#485=CARTESIAN_POINT('',(3.66162749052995,27.263630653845,-66.5745339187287));
#486=CARTESIAN_POINT('',(3.5143039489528,27.3644797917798,-66.5824920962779));
#487=CARTESIAN_POINT('',(3.21125854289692,27.5536868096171,-66.5977966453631));
#488=CARTESIAN_POINT('',(3.05551514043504,27.6420103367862,-66.6051413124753));
#489=CARTESIAN_POINT('',(2.73715757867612,27.8051781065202,-66.6189835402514));
#490=CARTESIAN_POINT('',(2.574545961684,27.880027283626,-66.6254814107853));
#491=CARTESIAN_POINT('',(2.24368612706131,28.0156892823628,-66.6374434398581));
#492=CARTESIAN_POINT('',(2.07544269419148,28.0765136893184,-66.6429084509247));
#493=CARTESIAN_POINT('',(1.73444942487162,28.1837480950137,-66.6526549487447));
#494=CARTESIAN_POINT('',(1.56170071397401,28.2301616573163,-66.6569367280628));
#495=CARTESIAN_POINT('',(1.15986202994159,28.3201191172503,-66.6652983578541));
#496=CARTESIAN_POINT('',(0.929590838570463,28.3585129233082,-66.6689221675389));
#497=CARTESIAN_POINT('',(0.466198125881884,28.4097522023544,-66.6737726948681));
#498=CARTESIAN_POINT('',(0.233076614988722,28.4225977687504,-66.6749994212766));
#499=CARTESIAN_POINT('',(0.,28.4226,-66.675));
#500=B_SPLINE_CURVE_WITH_KNOTS('',3,(#390,#391,#392,#393,#394,#395,#396,#397,#398,#399,#400,
#401,#402,#403,#404,#405,#406,#407,#408,#409,#410,#411,#412,#413,#414,#415,#416,#417,#418,#419,
#420,#421,#422,#423,#424,#425,#426,#427,#428,#429,#430,#431,#432,#433,#434,#435,#436,#437,#438,
#439,#440,#441,#442,#443,#444,#445,#446,#447,#448,#449,#450,#451,#452,#453,#454,#455,#456,#457,
#458,#459,#460,#461,#462,#463,#464,#465,#466,#467,#468,#469,#470,#471,#472,#473,#474,#475,#476,
#477,#478,#479,#480,#481,#482,#483,#484,#485,#486,#487,#488,#489,#490,#491,#492,#493,#494,#495,
#496,#497,#498,#499),.UNSPECIFIED.,.T.,.F.,(4,2,2,2,2,2,2,2,2,2,2,2,2,2,2,2,2,2,2,2,2,2,2,2,2,2,
2,2,2,2,2,2,2,2,2,2,2,2,2,2,2,2,2,2,2,2,2,2,2,2,2,2,2,2,4),(0.,0.533711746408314,
1.06755266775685,1.60182437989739,2.13629177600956,2.67024397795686,3.20439312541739,
3.73823428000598,4.2722731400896,4.80767187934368,5.34326850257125,5.87869227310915,
6.41431362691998,6.95076787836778,7.48742077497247,8.0238657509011,8.56050801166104,
9.62936083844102,10.6981880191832,11.7635043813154,12.8288339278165,13.8958932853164,
14.9629809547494,16.0343323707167,17.1056848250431,18.1772001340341,19.248686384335,
20.3159947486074,21.3832900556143,22.4485886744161,23.5139090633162,24.5824802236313,
25.6510756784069,26.7231543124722,27.7952194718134,28.8655564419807,29.9358658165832,
30.4694553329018,31.0028469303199,31.5364343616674,32.0698266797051,32.6033524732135,
33.1366834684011,33.6702022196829,34.2035272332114,34.7390984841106,35.2744740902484,
35.8101757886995,36.3456797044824,36.8826250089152,37.4193732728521,37.9556765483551,
38.49184709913,39.1908125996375,39.8897755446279),.UNSPECIFIED.);
#501=CARTESIAN_POINT('',(0.,28.4226,-66.675));
#502=VERTEX_POINT('',#501);
#503=EDGE_CURVE('E36',#502,#502,#500,.T.);
#504=ORIENTED_EDGE('',*,*,#503,.F.);
#505=EDGE_LOOP('',(#504));
#506=FACE_BOUND('',#505,.T.);
#507=CARTESIAN_POINT('',(6.35,22.0726,66.3719302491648));
#508=CARTESIAN_POINT('',(6.35000170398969,21.8946302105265,66.3719297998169));
#509=CARTESIAN_POINT('',(6.34251528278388,21.716686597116,66.372647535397));
#510=CARTESIAN_POINT('',(6.31262487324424,21.3620108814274,66.3754971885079));
#511=CARTESIAN_POINT('',(6.29021727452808,21.1852790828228,66.3776294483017));
#512=CARTESIAN_POINT('',(6.23061863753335,20.8342050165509,66.3832502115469));
#513=CARTESIAN_POINT('',(6.1934156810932,20.6598647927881,66.3867398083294));
#514=CARTESIAN_POINT('',(6.10448199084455,20.3148915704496,66.394976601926));
#515=CARTESIAN_POINT('',(6.05274594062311,20.1442599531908,66.3997242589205));
#516=CARTESIAN_POINT('',(5.93518374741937,19.8081436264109,66.4103357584));
#517=CARTESIAN_POINT('',(5.86937126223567,19.642654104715,66.416198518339));
#518=CARTESIAN_POINT('',(5.72407295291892,19.317755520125,66.4288787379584));
#519=CARTESIAN_POINT('',(5.64458209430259,19.1583487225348,66.4356965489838));
#520=CARTESIAN_POINT('',(5.47256108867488,18.8468897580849,66.4500875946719));
#521=CARTESIAN_POINT('',(5.38003848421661,18.6948334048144,66.457660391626));
#522=CARTESIAN_POINT('',(5.18253815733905,18.398985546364,66.4733535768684));
#523=CARTESIAN_POINT('',(5.07755583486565,18.2551971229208,66.4814741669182));
#524=CARTESIAN_POINT('',(4.85561718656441,17.976591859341,66.4980527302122));
#525=CARTESIAN_POINT('',(4.738630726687,17.8417990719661,66.5065115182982));
#526=CARTESIAN_POINT('',(4.49368817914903,17.5824899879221,66.5235106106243));
#527=CARTESIAN_POINT('',(4.36572805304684,17.457977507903,66.5320509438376));
#528=CARTESIAN_POINT('',(4.0998178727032,17.2201990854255,66.5489658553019));
#529=CARTESIAN_POINT('',(3.96187105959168,17.1069295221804,66.5573404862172));
#530=CARTESIAN_POINT('',(3.67686695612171,16.8923510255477,66.5736933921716));
#531=CARTESIAN_POINT('',(3.52980632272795,16.7910465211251,66.5816715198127));
#532=CARTESIAN_POINT('',(3.2274210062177,16.601020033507,66.5970143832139));
#533=CARTESIAN_POINT('',(3.07208398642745,16.5123175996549,66.6043781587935));
#534=CARTESIAN_POINT('',(2.7543970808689,16.3482858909,66.6182723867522));
#535=CARTESIAN_POINT('',(2.59204461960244,16.2729615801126,66.6248025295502));
#536=CARTESIAN_POINT('',(2.26158012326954,16.1362967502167,66.6368379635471));
#537=CARTESIAN_POINT('',(2.0934703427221,16.0749508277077,66.642343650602));
#538=CARTESIAN_POINT('',(1.75263022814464,15.9666335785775,66.6521799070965));
#539=CARTESIAN_POINT('',(1.57989821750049,15.9196675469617,66.656510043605));
#540=CARTESIAN_POINT('',(1.05779965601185,15.8012102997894,66.6675102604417));
#541=CARTESIAN_POINT('',(0.703147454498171,15.7515896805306,66.6722420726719));
#542=CARTESIAN_POINT('',(-0.00928768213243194,15.712578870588,66.6759527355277));
#543=CARTESIAN_POINT('',(-0.367070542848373,15.7231872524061,66.674931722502));
#544=CARTESIAN_POINT('',(-1.07462427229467,15.8041080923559,66.667274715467));
#545=CARTESIAN_POINT('',(-1.42441735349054,15.8742268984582,66.6606569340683));
#546=CARTESIAN_POINT('',(-2.10723358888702,16.0718976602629,66.6425686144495));
#547=CARTESIAN_POINT('',(-2.44025654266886,16.1994503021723,66.631098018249));
#548=CARTESIAN_POINT('',(-3.08070841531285,16.5085758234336,66.6045632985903));
#549=CARTESIAN_POINT('',(-3.38809556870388,16.6902347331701,66.5894934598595));
#550=CARTESIAN_POINT('',(-3.9680899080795,17.1023551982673,66.5574518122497));
#551=CARTESIAN_POINT('',(-4.24069616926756,17.3328180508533,66.54047995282));
#552=CARTESIAN_POINT('',(-4.7445256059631,17.8370941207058,66.5064602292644));
#553=CARTESIAN_POINT('',(-4.97558021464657,18.1110757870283,66.489412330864));
#554=CARTESIAN_POINT('',(-5.38844301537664,18.6940273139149,66.4572293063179));
#555=CARTESIAN_POINT('',(-5.57025114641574,19.0029972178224,66.4420941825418));
#556=CARTESIAN_POINT('',(-5.87945769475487,19.6472808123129,66.4154485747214));
#557=CARTESIAN_POINT('',(-6.00684620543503,19.982599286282,66.4039387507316));
#558=CARTESIAN_POINT('',(-6.20346661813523,20.6699998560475,66.3858604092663));
#559=CARTESIAN_POINT('',(-6.27270012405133,21.0220814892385,66.3792917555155));
#560=CARTESIAN_POINT('',(-6.35082946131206,21.7315356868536,66.3718626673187));
#561=CARTESIAN_POINT('',(-6.35996088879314,22.0888820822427,66.3709799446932));
#562=CARTESIAN_POINT('',(-6.31824509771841,22.8000201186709,66.3749638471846));
#563=CARTESIAN_POINT('',(-6.26739861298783,23.1538118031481,66.3798304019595));
#564=CARTESIAN_POINT('',(-6.10736726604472,23.8471140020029,66.3947442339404));
#565=CARTESIAN_POINT('',(-5.99829336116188,24.1866503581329,66.4047816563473));
#566=CARTESIAN_POINT('',(-5.72501642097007,24.842606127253,66.4288982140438));
#567=CARTESIAN_POINT('',(-5.56081223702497,25.1590250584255,66.4429774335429));
#568=CARTESIAN_POINT('',(-5.18134422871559,25.7608391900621,66.4736452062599));
#569=CARTESIAN_POINT('',(-4.96592401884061,26.0461353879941,66.4902413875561));
#570=CARTESIAN_POINT('',(-4.49036234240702,26.5766024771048,66.5240478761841));
#571=CARTESIAN_POINT('',(-4.23021987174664,26.8217724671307,66.5412581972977));
#572=CARTESIAN_POINT('',(-3.671582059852,27.2658380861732,66.5744209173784));
#573=CARTESIAN_POINT('',(-3.37296441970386,27.4645802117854,66.5903690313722));
#574=CARTESIAN_POINT('',(-2.74644084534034,27.8090913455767,66.619147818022));
#575=CARTESIAN_POINT('',(-2.41853527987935,27.9548610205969,66.6319785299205));
#576=CARTESIAN_POINT('',(-1.74335057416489,28.1890350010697,66.6530589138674));
#577=CARTESIAN_POINT('',(-1.39610397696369,28.2775326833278,66.6613160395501));
#578=CARTESIAN_POINT('',(-0.691402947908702,28.3949301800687,66.6723436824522));
#579=CARTESIAN_POINT('',(-0.333948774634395,28.4238315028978,66.6751143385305));
#580=CARTESIAN_POINT('',(0.200997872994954,28.4219234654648,66.6749370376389));
#581=CARTESIAN_POINT('',(0.378850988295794,28.4137884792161,66.6741599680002));
#582=CARTESIAN_POINT('',(0.733218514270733,28.3826289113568,66.6712029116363));
#583=CARTESIAN_POINT('',(0.909733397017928,28.3596098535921,66.6690234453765));
#584=CARTESIAN_POINT('',(1.26023858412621,28.2988319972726,66.6633196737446));
#585=CARTESIAN_POINT('',(1.43422793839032,28.2610677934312,66.6597948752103));
#586=CARTESIAN_POINT('',(1.77833532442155,28.1710942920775,66.6515022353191));
#587=CARTESIAN_POINT('',(1.94845474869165,28.1188902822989,66.6467348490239));
#588=CARTESIAN_POINT('',(2.28372464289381,28.0003924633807,66.6360890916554));
#589=CARTESIAN_POINT('',(2.44887385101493,27.934095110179,66.6302104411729));
#590=CARTESIAN_POINT('',(2.77293850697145,27.7879211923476,66.6175106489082));
#591=CARTESIAN_POINT('',(2.93185620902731,27.7080495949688,66.6106898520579));
#592=CARTESIAN_POINT('',(3.24246328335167,27.5352483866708,66.5962929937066));
#593=CARTESIAN_POINT('',(3.39415009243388,27.4423141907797,66.5887166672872));
#594=CARTESIAN_POINT('',(3.68912226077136,27.2441026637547,66.5730261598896));
#595=CARTESIAN_POINT('',(3.83241065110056,27.1388298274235,66.5649121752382));
#596=CARTESIAN_POINT('',(4.11022617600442,26.9161895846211,66.548336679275));
#597=CARTESIAN_POINT('',(4.24471428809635,26.7987735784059,66.5398738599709));
#598=CARTESIAN_POINT('',(4.50328053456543,26.5530863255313,66.5228748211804));
#599=CARTESIAN_POINT('',(4.62736245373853,26.4248190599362,66.5143386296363));
#600=CARTESIAN_POINT('',(4.86437141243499,26.1582117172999,66.4974258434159));
#601=CARTESIAN_POINT('',(4.97729160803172,26.0198655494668,66.489049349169));
#602=CARTESIAN_POINT('',(5.19105374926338,25.7341945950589,66.4727017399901));
#603=CARTESIAN_POINT('',(5.29190013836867,25.5868731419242,66.464730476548));
#604=CARTESIAN_POINT('',(5.48110399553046,25.2838292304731,66.4493954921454));
#605=CARTESIAN_POINT('',(5.56942684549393,25.1280850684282,66.4420334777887));
#606=CARTESIAN_POINT('',(5.73259317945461,24.8097260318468,66.4281544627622));
#607=CARTESIAN_POINT('',(5.80744159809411,24.6471136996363,66.4216371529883));
#608=CARTESIAN_POINT('',(5.9431020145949,24.3162524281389,66.4096363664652));
#609=CARTESIAN_POINT('',(6.00392560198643,24.148008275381,66.4041520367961));
#610=CARTESIAN_POINT('',(6.11115831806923,23.8070134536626,66.3943691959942));
#611=CARTESIAN_POINT('',(6.15757101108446,23.6342639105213,66.3900703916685));
#612=CARTESIAN_POINT('',(6.24752471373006,23.2324305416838,66.3816745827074));
#613=CARTESIAN_POINT('',(6.28591641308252,23.0021656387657,66.3780350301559));
#614=CARTESIAN_POINT('',(6.33715289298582,22.5387855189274,66.3731631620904));
#615=CARTESIAN_POINT('',(6.3499977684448,22.3056703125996,66.3719308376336));
#616=CARTESIAN_POINT('',(6.35,22.0726,66.3719302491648));
#617=B_SPLINE_CURVE_WITH_KNOTS('',3,(#507,#508,#509,#510,#511,#512,#513,#514,#515,#516,#517,
#518,#519,#520,#521,#522,#523,#524,#525,#526,#527,#528,#529,#530,#531,#532,#533,#534,#535,#536,
#537,#538,#539,#540,#541,#542,#543,#544,#545,#546,#547,#548,#549,#550,#551,#552,#553,#554,#555,
#556,#557,#558,#559,#560,#561,#562,#563,#564,#565,#566,#567,#568,#569,#570,#571,#572,#573,#574,
#575,#576,#577,#578,#579,#580,#581,#582,#583,#584,#585,#586,#587,#588,#589,#590,#591,#592,#593,
#594,#595,#596,#597,#598,#599,#600,#601,#602,#603,#604,#605,#606,#607,#608,#609,#610,#611,#612,
#613,#614,#615,#616),.UNSPECIFIED.,.T.,.F.,(4,2,2,2,2,2,2,2,2,2,2,2,2,2,2,2,2,2,2,2,2,2,2,2,2,2,
2,2,2,2,2,2,2,2,2,2,2,2,2,2,2,2,2,2,2,2,2,2,2,2,2,2,2,2,4),(0.,0.533705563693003,
1.06754031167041,1.6018059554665,2.13626729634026,2.67021240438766,3.20435445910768,
3.73818862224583,4.27222049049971,4.80762735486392,5.34323210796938,5.87866380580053,
6.41429308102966,6.95074440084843,7.48739436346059,8.02383652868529,8.56047598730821,
9.62932105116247,10.6981407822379,11.7634957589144,12.8288634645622,13.8959342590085,
14.9630334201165,16.0343684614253,17.1057048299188,18.1772361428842,19.2487379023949,
20.3160369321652,21.383322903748,22.4485822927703,23.5138638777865,24.5824409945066,
25.651042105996,26.7231278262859,27.7952000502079,28.8655199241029,29.9358127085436,
30.4694158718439,31.0028211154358,31.5364220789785,32.0698279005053,32.603368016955,
33.1367133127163,33.6702462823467,34.2035854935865,34.7391485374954,35.274515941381,
35.8102096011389,36.3457055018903,36.8826539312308,37.4194053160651,37.9557115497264,
38.4918850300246,39.1908316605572,39.8897756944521),.UNSPECIFIED.);
#618=CARTESIAN_POINT('',(6.35,22.0726,66.3719302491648));
#619=VERTEX_POINT('',#618);
#620=EDGE_CURVE('E162',#619,#619,#617,.T.);
#621=ORIENTED_EDGE('',*,*,#620,.F.);
#622=EDGE_LOOP('',(#621));
#623=FACE_BOUND('',#622,.T.);
#624=DIRECTION('',(0.,-1.,0.));
#625=VECTOR('',#624,1.);
#626=CARTESIAN_POINT('',(-19.05,50.4952,63.8956424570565));
#627=LINE('',#626,#625);
#628=CARTESIAN_POINT('',(-19.05,37.7952,63.8956424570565));
#629=VERTEX_POINT('',#628);
#630=EDGE_CURVE('E11',#629,#44,#627,.F.);
#631=ORIENTED_EDGE('',*,*,#630,.F.);
#632=CARTESIAN_POINT('',(0.,37.7952,0.));
#633=DIRECTION('',(0.,-1.,0.));
#634=DIRECTION('',(1.,0.,0.));
#635=AXIS2_PLACEMENT_3D('',#632,#633,#634);
#636=CIRCLE('',#635,66.675);
#637=CARTESIAN_POINT('',(19.05,37.7952,63.8956424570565));
#638=VERTEX_POINT('',#637);
#639=EDGE_CURVE('E158',#638,#629,#636,.T.);
#640=ORIENTED_EDGE('',*,*,#639,.F.);
#641=DIRECTION('',(0.,-1.,0.));
#642=VECTOR('',#641,1.);
#643=CARTESIAN_POINT('',(19.05,50.4952,63.8956424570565));
#644=LINE('',#643,#642);
#645=EDGE_CURVE('E45',#363,#638,#644,.T.);
#646=ORIENTED_EDGE('',*,*,#645,.F.);
#647=ORIENTED_EDGE('',*,*,#371,.T.);
#648=DIRECTION('',(0.,-1.,0.));
#649=VECTOR('',#648,1.);
#650=CARTESIAN_POINT('',(19.05,50.4952,-63.8956424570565));
#651=LINE('',#650,#649);
#652=CARTESIAN_POINT('',(19.05,37.7952,-63.8956424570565));
#653=VERTEX_POINT('',#652);
#654=EDGE_CURVE('E157',#653,#368,#651,.F.);
#655=ORIENTED_EDGE('',*,*,#654,.F.);
#656=CARTESIAN_POINT('',(-19.05,37.7952,-63.8956424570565));
#657=VERTEX_POINT('',#656);
#658=EDGE_CURVE('E125',#657,#653,#636,.T.);
#659=ORIENTED_EDGE('',*,*,#658,.F.);
#660=DIRECTION('',(0.,-1.,0.));
#661=VECTOR('',#660,1.);
#662=CARTESIAN_POINT('',(-19.05,50.4952,-63.8956424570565));
#663=LINE('',#662,#661);
#664=EDGE_CURVE('E160',#31,#657,#663,.T.);
#665=ORIENTED_EDGE('',*,*,#664,.F.);
#666=ORIENTED_EDGE('',*,*,#52,.T.);
#667=EDGE_LOOP('',(#631,#640,#646,#647,#655,#659,#665,#666));
#668=FACE_BOUND('',#667,.T.);
#669=CARTESIAN_POINT('',(0.,3.175,0.));
#670=DIRECTION('',(0.,1.,0.));
#671=DIRECTION('',(0.,0.,1.));
#672=AXIS2_PLACEMENT_3D('',#669,#670,#671);
#673=CIRCLE('',#672,66.675);
#674=CARTESIAN_POINT('',(0.,3.175,66.675));
#675=VERTEX_POINT('',#674);
#676=EDGE_CURVE('E142',#675,#675,#673,.T.);
#677=ORIENTED_EDGE('',*,*,#676,.F.);
#678=EDGE_LOOP('',(#677));
#679=FACE_BOUND('',#678,.T.);
#680=ADVANCED_FACE('F166',(#506,#623,#668,#679),#389,.F.);
#681=CARTESIAN_POINT('',(0.,3.175,0.));
#682=DIRECTION('',(0.,1.,0.));
#683=DIRECTION('',(0.,0.,1.));
#684=AXIS2_PLACEMENT_3D('',#681,#682,#683);
#685=PLANE('',#684);
#686=ORIENTED_EDGE('',*,*,#676,.T.);
#687=EDGE_LOOP('',(#686));
#688=FACE_BOUND('',#687,.T.);
#689=ADVANCED_FACE('F213',(#688),#685,.T.);
#690=CARTESIAN_POINT('',(-19.05,37.7952,-69.85));
#691=DIRECTION('',(0.,-1.,0.));
#692=DIRECTION('',(1.,0.,0.));
#693=AXIS2_PLACEMENT_3D('',#690,#691,#692);
#694=PLANE('',#693);
#695=DIRECTION('',(0.,0.,1.));
#696=VECTOR('',#695,1.);
#697=CARTESIAN_POINT('',(-19.05,37.7952,-69.85));
#698=LINE('',#697,#696);
#699=EDGE_CURVE('E61',#331,#657,#698,.T.);
#700=ORIENTED_EDGE('',*,*,#699,.T.);
#701=ORIENTED_EDGE('',*,*,#658,.T.);
#702=DIRECTION('',(0.,0.,1.));
#703=VECTOR('',#702,1.);
#704=CARTESIAN_POINT('',(19.05,37.7952,-69.85));
#705=LINE('',#704,#703);
#706=EDGE_CURVE('E117',#335,#653,#705,.T.);
#707=ORIENTED_EDGE('',*,*,#706,.F.);
#708=ORIENTED_EDGE('',*,*,#336,.F.);
#709=EDGE_LOOP('',(#700,#701,#707,#708));
#710=FACE_BOUND('',#709,.T.);
#711=ADVANCED_FACE('F123',(#710),#694,.F.);
#712=CARTESIAN_POINT('',(19.05,50.4952,-69.85));
#713=DIRECTION('',(1.,0.,0.));
#714=DIRECTION('',(0.,1.,0.));
#715=AXIS2_PLACEMENT_3D('',#712,#713,#714);
#716=PLANE('',#715);
#717=ORIENTED_EDGE('',*,*,#706,.T.);
#718=ORIENTED_EDGE('',*,*,#654,.T.);
#719=ORIENTED_EDGE('',*,*,#369,.F.);
#720=ORIENTED_EDGE('',*,*,#342,.F.);
#721=EDGE_LOOP('',(#717,#718,#719,#720));
#722=FACE_BOUND('',#721,.T.);
#723=ADVANCED_FACE('F116',(#722),#716,.F.);
#724=CARTESIAN_POINT('',(-19.05,50.4952,-69.85));
#725=DIRECTION('',(-1.,0.,0.));
#726=DIRECTION('',(0.,-1.,0.));
#727=AXIS2_PLACEMENT_3D('',#724,#725,#726);
#728=PLANE('',#727);
#729=ORIENTED_EDGE('',*,*,#32,.T.);
#730=ORIENTED_EDGE('',*,*,#664,.T.);
#731=ORIENTED_EDGE('',*,*,#699,.F.);
#732=ORIENTED_EDGE('',*,*,#332,.F.);
#733=EDGE_LOOP('',(#729,#730,#731,#732));
#734=FACE_BOUND('',#733,.T.);
#735=ADVANCED_FACE('F259',(#734),#728,.F.);
#736=EDGE_CURVE('E132',#629,#316,#698,.T.);
#737=ORIENTED_EDGE('',*,*,#736,.F.);
#738=ORIENTED_EDGE('',*,*,#630,.T.);
#739=ORIENTED_EDGE('',*,*,#45,.T.);
#740=ORIENTED_EDGE('',*,*,#323,.F.);
#741=EDGE_LOOP('',(#737,#738,#739,#740));
#742=FACE_BOUND('',#741,.T.);
#743=ADVANCED_FACE('F204',(#742),#728,.F.);
#744=ORIENTED_EDGE('',*,*,#364,.F.);
#745=ORIENTED_EDGE('',*,*,#645,.T.);
#746=EDGE_CURVE('E53',#638,#307,#705,.T.);
#747=ORIENTED_EDGE('',*,*,#746,.T.);
#748=ORIENTED_EDGE('',*,*,#308,.F.);
#749=EDGE_LOOP('',(#744,#745,#747,#748));
#750=FACE_BOUND('',#749,.T.);
#751=ADVANCED_FACE('F176',(#750),#716,.F.);
#752=ORIENTED_EDGE('',*,*,#746,.F.);
#753=ORIENTED_EDGE('',*,*,#639,.T.);
#754=ORIENTED_EDGE('',*,*,#736,.T.);
#755=ORIENTED_EDGE('',*,*,#317,.F.);
#756=EDGE_LOOP('',(#752,#753,#754,#755));
#757=FACE_BOUND('',#756,.T.);
#758=ADVANCED_FACE('F205',(#757),#694,.F.);
#759=CARTESIAN_POINT('',(0.,22.0726,-69.85));
#760=DIRECTION('',(0.,0.,1.));
#761=DIRECTION('',(1.,0.,0.));
#762=AXIS2_PLACEMENT_3D('',#759,#760,#761);
#763=CYLINDRICAL_SURFACE('',#762,6.35);
#764=ORIENTED_EDGE('',*,*,#620,.T.);
#765=EDGE_LOOP('',(#764));
#766=FACE_BOUND('',#765,.T.);
#767=ORIENTED_EDGE('',*,*,#292,.F.);
#768=EDGE_LOOP('',(#767));
#769=FACE_BOUND('',#768,.T.);
#770=ADVANCED_FACE('F174',(#766,#769),#763,.F.);
#771=ORIENTED_EDGE('',*,*,#503,.T.);
#772=EDGE_LOOP('',(#771));
#773=FACE_BOUND('',#772,.T.);
#774=ORIENTED_EDGE('',*,*,#175,.F.);
#775=EDGE_LOOP('',(#774));
#776=FACE_BOUND('',#775,.T.);
#777=ADVANCED_FACE('F170',(#773,#776),#763,.F.);
#778=CLOSED_SHELL('',(#56,#357,#375,#384,#680,#689,#711,#723,#735,#743,#751,#758,#770,#777));
#779=MANIFOLD_SOLID_BREP('B2',#778);
#780=ADVANCED_BREP_SHAPE_REPRESENTATION('',(#18,#779),#14);
#781=SHAPE_DEFINITION_REPRESENTATION(#9,#780);
ENDSEC;
END-ISO-10303-21;
